One B-rep face of a CAD part: STEP entity #1675.
In plain terms, the planar face has unit normal (1, 0, 0).
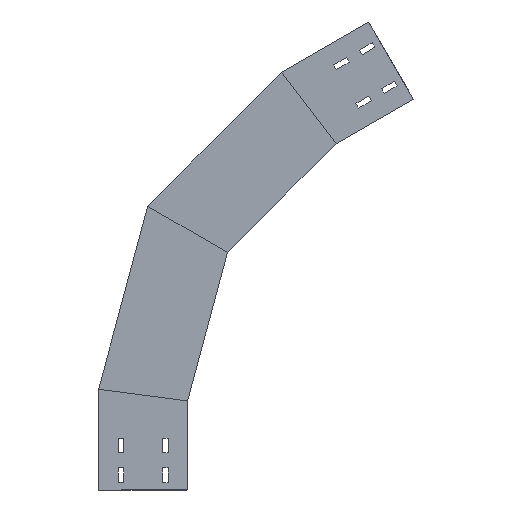
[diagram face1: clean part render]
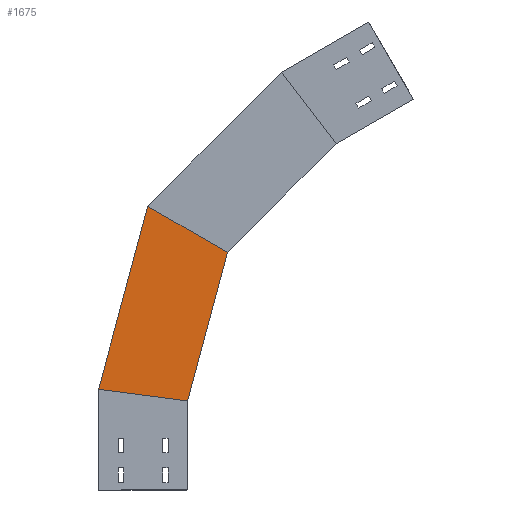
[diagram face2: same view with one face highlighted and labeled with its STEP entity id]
Its self-contained STEP definition (entity closure, numbers rounded to 3 decimals):
#32 = CARTESIAN_POINT ( 'NONE',  ( 0., 70.365, 474.908 ) ) ;
#94 = ORIENTED_EDGE ( 'NONE', *, *, #151, .T. ) ;
#104 = VERTEX_POINT ( 'NONE', #2150 ) ;
#137 = VECTOR ( 'NONE', #2205, 1000. ) ;
#151 = EDGE_CURVE ( 'NONE', #1754, #104, #2175, .T. ) ;
#221 = FACE_OUTER_BOUND ( 'NONE', #1505, .T. ) ;
#282 = EDGE_CURVE ( 'NONE', #443, #104, #1195, .T. ) ;
#368 = DIRECTION ( 'NONE',  ( 0., 0., -1. ) ) ;
#372 = EDGE_CURVE ( 'NONE', #1793, #443, #1171, .T. ) ;
#380 = CARTESIAN_POINT ( 'NONE',  ( 0., -158.073, 703.345 ) ) ;
#409 = VECTOR ( 'NONE', #1973, 1000. ) ;
#443 = VERTEX_POINT ( 'NONE', #1403 ) ;
#596 = VECTOR ( 'NONE', #1408, 1000. ) ;
#627 = CARTESIAN_POINT ( 'NONE',  ( 0., -274.276, 551.906 ) ) ;
#719 = CARTESIAN_POINT ( 'NONE',  ( 0., 67.452, 477.821 ) ) ;
#808 = CARTESIAN_POINT ( 'NONE',  ( 0., -35.701, 368.842 ) ) ;
#883 = EDGE_CURVE ( 'NONE', #1793, #1754, #1554, .T. ) ;
#1066 = AXIS2_PLACEMENT_3D ( 'NONE', #1915, #1902, #368 ) ;
#1171 = LINE ( 'NONE', #1859, #137 ) ;
#1195 = LINE ( 'NONE', #808, #2118 ) ;
#1237 = PLANE ( 'NONE',  #1066 ) ;
#1366 = DIRECTION ( 'NONE',  ( 0., -0.707, 0.707 ) ) ;
#1367 = ORIENTED_EDGE ( 'NONE', *, *, #883, .T. ) ;
#1403 = CARTESIAN_POINT ( 'NONE',  ( 0., -67.034, 400.175 ) ) ;
#1408 = DIRECTION ( 'NONE',  ( 0., -0.707, 0.707 ) ) ;
#1505 = EDGE_LOOP ( 'NONE', ( #1367, #94, #2140, #2127 ) ) ;
#1554 = LINE ( 'NONE', #32, #596 ) ;
#1675 = ADVANCED_FACE ( 'NONE', ( #221 ), #1237, .T. ) ;
#1754 = VERTEX_POINT ( 'NONE', #380 ) ;
#1793 = VERTEX_POINT ( 'NONE', #719 ) ;
#1859 = CARTESIAN_POINT ( 'NONE',  ( 0., -129.979, 363.834 ) ) ;
#1902 = DIRECTION ( 'NONE',  ( 1., 0., 0. ) ) ;
#1915 = CARTESIAN_POINT ( 'NONE',  ( 0., -35.701, 368.842 ) ) ;
#1973 = DIRECTION ( 'NONE',  ( 0., -0.609, -0.793 ) ) ;
#2118 = VECTOR ( 'NONE', #1366, 1000. ) ;
#2127 = ORIENTED_EDGE ( 'NONE', *, *, #372, .F. ) ;
#2140 = ORIENTED_EDGE ( 'NONE', *, *, #282, .F. ) ;
#2150 = CARTESIAN_POINT ( 'NONE',  ( 0., -250.175, 583.315 ) ) ;
#2175 = LINE ( 'NONE', #627, #409 ) ;
#2205 = DIRECTION ( 'NONE',  ( 0., -0.866, -0.5 ) ) ;
